# Generated deterministically by seda-macro-lef-normalizer-v1; recipe orfs-ng45-fakeram-metal3-coupledl2-pg-v1.
VERSION 5.8 ;
BUSBITCHARS "[]" ;
DIVIDERCHAR "/" ;

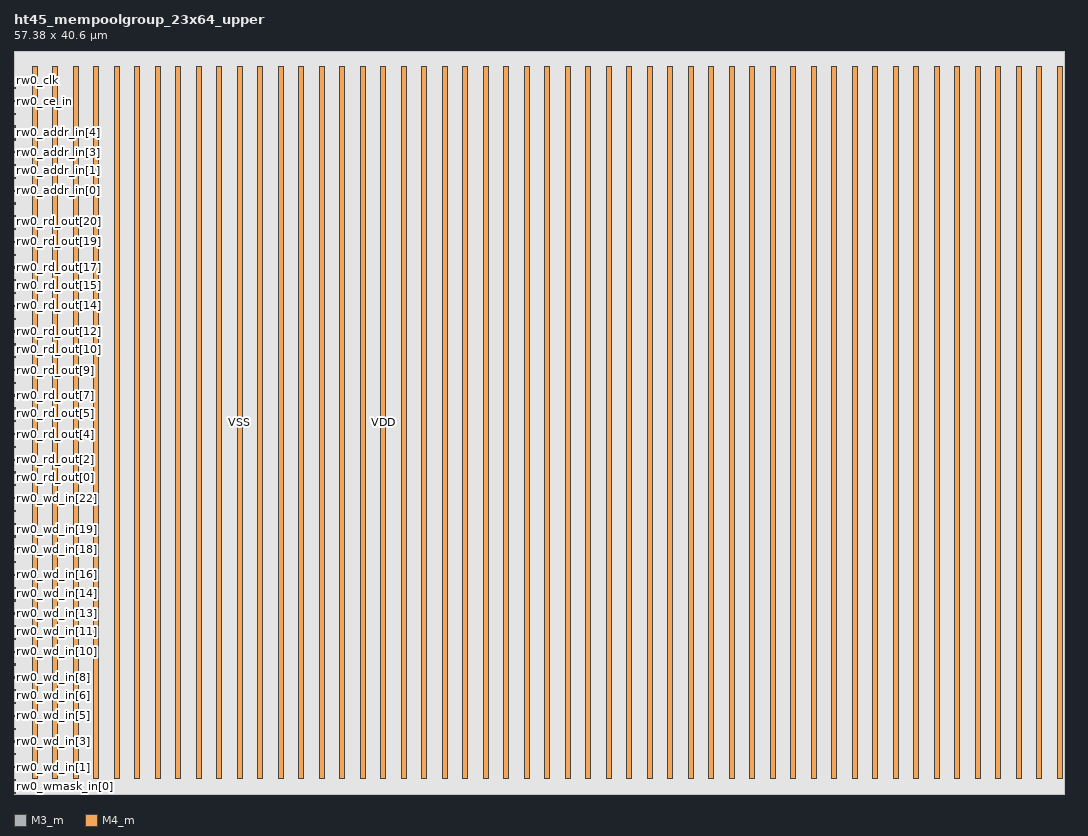
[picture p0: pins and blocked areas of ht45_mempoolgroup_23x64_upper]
MACRO ht45_mempoolgroup_23x64_upper
  FOREIGN ht45_mempoolgroup_23x64_upper 0 0 ;
  CLASS COVER ;
  ORIGIN 0 0 ;
  SIZE 57.38 BY 40.6 ;
  SYMMETRY X Y R90 ;
  PIN rw0_wmask_in[0]
    DIRECTION INPUT ;
    USE SIGNAL ;
    SHAPE ABUTMENT ;
    PORT
      LAYER M3_m ;
      RECT 0 0.035 0.07 0.105 ;
    END
  END rw0_wmask_in[0]
  PIN rw0_wd_in[0]
    DIRECTION INPUT ;
    USE SIGNAL ;
    SHAPE ABUTMENT ;
    PORT
      LAYER M3_m ;
      RECT 0 0.735 0.07 0.805 ;
    END
  END rw0_wd_in[0]
  PIN rw0_wd_in[1]
    DIRECTION INPUT ;
    USE SIGNAL ;
    SHAPE ABUTMENT ;
    PORT
      LAYER M3_m ;
      RECT 0 1.435 0.07 1.505 ;
    END
  END rw0_wd_in[1]
  PIN rw0_wd_in[2]
    DIRECTION INPUT ;
    USE SIGNAL ;
    SHAPE ABUTMENT ;
    PORT
      LAYER M3_m ;
      RECT 0 2.135 0.07 2.205 ;
    END
  END rw0_wd_in[2]
  PIN rw0_wd_in[3]
    DIRECTION INPUT ;
    USE SIGNAL ;
    SHAPE ABUTMENT ;
    PORT
      LAYER M3_m ;
      RECT 0 2.835 0.07 2.905 ;
    END
  END rw0_wd_in[3]
  PIN rw0_wd_in[4]
    DIRECTION INPUT ;
    USE SIGNAL ;
    SHAPE ABUTMENT ;
    PORT
      LAYER M3_m ;
      RECT 0 3.535 0.07 3.605 ;
    END
  END rw0_wd_in[4]
  PIN rw0_wd_in[5]
    DIRECTION INPUT ;
    USE SIGNAL ;
    SHAPE ABUTMENT ;
    PORT
      LAYER M3_m ;
      RECT 0 4.235 0.07 4.305 ;
    END
  END rw0_wd_in[5]
  PIN rw0_wd_in[6]
    DIRECTION INPUT ;
    USE SIGNAL ;
    SHAPE ABUTMENT ;
    PORT
      LAYER M3_m ;
      RECT 0 4.935 0.07 5.005 ;
    END
  END rw0_wd_in[6]
  PIN rw0_wd_in[7]
    DIRECTION INPUT ;
    USE SIGNAL ;
    SHAPE ABUTMENT ;
    PORT
      LAYER M3_m ;
      RECT 0 5.635 0.07 5.705 ;
    END
  END rw0_wd_in[7]
  PIN rw0_wd_in[8]
    DIRECTION INPUT ;
    USE SIGNAL ;
    SHAPE ABUTMENT ;
    PORT
      LAYER M3_m ;
      RECT 0 6.335 0.07 6.405 ;
    END
  END rw0_wd_in[8]
  PIN rw0_wd_in[9]
    DIRECTION INPUT ;
    USE SIGNAL ;
    SHAPE ABUTMENT ;
    PORT
      LAYER M3_m ;
      RECT 0 7.035 0.07 7.105 ;
    END
  END rw0_wd_in[9]
  PIN rw0_wd_in[10]
    DIRECTION INPUT ;
    USE SIGNAL ;
    SHAPE ABUTMENT ;
    PORT
      LAYER M3_m ;
      RECT 0 7.735 0.07 7.805 ;
    END
  END rw0_wd_in[10]
  PIN rw0_wd_in[11]
    DIRECTION INPUT ;
    USE SIGNAL ;
    SHAPE ABUTMENT ;
    PORT
      LAYER M3_m ;
      RECT 0 8.435 0.07 8.505 ;
    END
  END rw0_wd_in[11]
  PIN rw0_wd_in[12]
    DIRECTION INPUT ;
    USE SIGNAL ;
    SHAPE ABUTMENT ;
    PORT
      LAYER M3_m ;
      RECT 0 9.135 0.07 9.205 ;
    END
  END rw0_wd_in[12]
  PIN rw0_wd_in[13]
    DIRECTION INPUT ;
    USE SIGNAL ;
    SHAPE ABUTMENT ;
    PORT
      LAYER M3_m ;
      RECT 0 9.835 0.07 9.905 ;
    END
  END rw0_wd_in[13]
  PIN rw0_wd_in[14]
    DIRECTION INPUT ;
    USE SIGNAL ;
    SHAPE ABUTMENT ;
    PORT
      LAYER M3_m ;
      RECT 0 10.535 0.07 10.605 ;
    END
  END rw0_wd_in[14]
  PIN rw0_wd_in[15]
    DIRECTION INPUT ;
    USE SIGNAL ;
    SHAPE ABUTMENT ;
    PORT
      LAYER M3_m ;
      RECT 0 11.235 0.07 11.305 ;
    END
  END rw0_wd_in[15]
  PIN rw0_wd_in[16]
    DIRECTION INPUT ;
    USE SIGNAL ;
    SHAPE ABUTMENT ;
    PORT
      LAYER M3_m ;
      RECT 0 11.935 0.07 12.005 ;
    END
  END rw0_wd_in[16]
  PIN rw0_wd_in[17]
    DIRECTION INPUT ;
    USE SIGNAL ;
    SHAPE ABUTMENT ;
    PORT
      LAYER M3_m ;
      RECT 0 12.635 0.07 12.705 ;
    END
  END rw0_wd_in[17]
  PIN rw0_wd_in[18]
    DIRECTION INPUT ;
    USE SIGNAL ;
    SHAPE ABUTMENT ;
    PORT
      LAYER M3_m ;
      RECT 0 13.335 0.07 13.405 ;
    END
  END rw0_wd_in[18]
  PIN rw0_wd_in[19]
    DIRECTION INPUT ;
    USE SIGNAL ;
    SHAPE ABUTMENT ;
    PORT
      LAYER M3_m ;
      RECT 0 14.035 0.07 14.105 ;
    END
  END rw0_wd_in[19]
  PIN rw0_wd_in[20]
    DIRECTION INPUT ;
    USE SIGNAL ;
    SHAPE ABUTMENT ;
    PORT
      LAYER M3_m ;
      RECT 0 14.735 0.07 14.805 ;
    END
  END rw0_wd_in[20]
  PIN rw0_wd_in[21]
    DIRECTION INPUT ;
    USE SIGNAL ;
    SHAPE ABUTMENT ;
    PORT
      LAYER M3_m ;
      RECT 0 15.435 0.07 15.505 ;
    END
  END rw0_wd_in[21]
  PIN rw0_wd_in[22]
    DIRECTION INPUT ;
    USE SIGNAL ;
    SHAPE ABUTMENT ;
    PORT
      LAYER M3_m ;
      RECT 0 16.135 0.07 16.205 ;
    END
  END rw0_wd_in[22]
  PIN rw0_rd_out[0]
    DIRECTION OUTPUT ;
    USE SIGNAL ;
    SHAPE ABUTMENT ;
    PORT
      LAYER M3_m ;
      RECT 0 16.835 0.07 16.905 ;
    END
  END rw0_rd_out[0]
  PIN rw0_rd_out[1]
    DIRECTION OUTPUT ;
    USE SIGNAL ;
    SHAPE ABUTMENT ;
    PORT
      LAYER M3_m ;
      RECT 0 17.535 0.07 17.605 ;
    END
  END rw0_rd_out[1]
  PIN rw0_rd_out[2]
    DIRECTION OUTPUT ;
    USE SIGNAL ;
    SHAPE ABUTMENT ;
    PORT
      LAYER M3_m ;
      RECT 0 18.235 0.07 18.305 ;
    END
  END rw0_rd_out[2]
  PIN rw0_rd_out[3]
    DIRECTION OUTPUT ;
    USE SIGNAL ;
    SHAPE ABUTMENT ;
    PORT
      LAYER M3_m ;
      RECT 0 18.935 0.07 19.005 ;
    END
  END rw0_rd_out[3]
  PIN rw0_rd_out[4]
    DIRECTION OUTPUT ;
    USE SIGNAL ;
    SHAPE ABUTMENT ;
    PORT
      LAYER M3_m ;
      RECT 0 19.635 0.07 19.705 ;
    END
  END rw0_rd_out[4]
  PIN rw0_rd_out[5]
    DIRECTION OUTPUT ;
    USE SIGNAL ;
    SHAPE ABUTMENT ;
    PORT
      LAYER M3_m ;
      RECT 0 20.335 0.07 20.405 ;
    END
  END rw0_rd_out[5]
  PIN rw0_rd_out[6]
    DIRECTION OUTPUT ;
    USE SIGNAL ;
    SHAPE ABUTMENT ;
    PORT
      LAYER M3_m ;
      RECT 0 21.035 0.07 21.105 ;
    END
  END rw0_rd_out[6]
  PIN rw0_rd_out[7]
    DIRECTION OUTPUT ;
    USE SIGNAL ;
    SHAPE ABUTMENT ;
    PORT
      LAYER M3_m ;
      RECT 0 21.735 0.07 21.805 ;
    END
  END rw0_rd_out[7]
  PIN rw0_rd_out[8]
    DIRECTION OUTPUT ;
    USE SIGNAL ;
    SHAPE ABUTMENT ;
    PORT
      LAYER M3_m ;
      RECT 0 22.435 0.07 22.505 ;
    END
  END rw0_rd_out[8]
  PIN rw0_rd_out[9]
    DIRECTION OUTPUT ;
    USE SIGNAL ;
    SHAPE ABUTMENT ;
    PORT
      LAYER M3_m ;
      RECT 0 23.135 0.07 23.205 ;
    END
  END rw0_rd_out[9]
  PIN rw0_rd_out[10]
    DIRECTION OUTPUT ;
    USE SIGNAL ;
    SHAPE ABUTMENT ;
    PORT
      LAYER M3_m ;
      RECT 0 23.835 0.07 23.905 ;
    END
  END rw0_rd_out[10]
  PIN rw0_rd_out[11]
    DIRECTION OUTPUT ;
    USE SIGNAL ;
    SHAPE ABUTMENT ;
    PORT
      LAYER M3_m ;
      RECT 0 24.535 0.07 24.605 ;
    END
  END rw0_rd_out[11]
  PIN rw0_rd_out[12]
    DIRECTION OUTPUT ;
    USE SIGNAL ;
    SHAPE ABUTMENT ;
    PORT
      LAYER M3_m ;
      RECT 0 25.235 0.07 25.305 ;
    END
  END rw0_rd_out[12]
  PIN rw0_rd_out[13]
    DIRECTION OUTPUT ;
    USE SIGNAL ;
    SHAPE ABUTMENT ;
    PORT
      LAYER M3_m ;
      RECT 0 25.935 0.07 26.005 ;
    END
  END rw0_rd_out[13]
  PIN rw0_rd_out[14]
    DIRECTION OUTPUT ;
    USE SIGNAL ;
    SHAPE ABUTMENT ;
    PORT
      LAYER M3_m ;
      RECT 0 26.635 0.07 26.705 ;
    END
  END rw0_rd_out[14]
  PIN rw0_rd_out[15]
    DIRECTION OUTPUT ;
    USE SIGNAL ;
    SHAPE ABUTMENT ;
    PORT
      LAYER M3_m ;
      RECT 0 27.335 0.07 27.405 ;
    END
  END rw0_rd_out[15]
  PIN rw0_rd_out[16]
    DIRECTION OUTPUT ;
    USE SIGNAL ;
    SHAPE ABUTMENT ;
    PORT
      LAYER M3_m ;
      RECT 0 28.035 0.07 28.105 ;
    END
  END rw0_rd_out[16]
  PIN rw0_rd_out[17]
    DIRECTION OUTPUT ;
    USE SIGNAL ;
    SHAPE ABUTMENT ;
    PORT
      LAYER M3_m ;
      RECT 0 28.735 0.07 28.805 ;
    END
  END rw0_rd_out[17]
  PIN rw0_rd_out[18]
    DIRECTION OUTPUT ;
    USE SIGNAL ;
    SHAPE ABUTMENT ;
    PORT
      LAYER M3_m ;
      RECT 0 29.435 0.07 29.505 ;
    END
  END rw0_rd_out[18]
  PIN rw0_rd_out[19]
    DIRECTION OUTPUT ;
    USE SIGNAL ;
    SHAPE ABUTMENT ;
    PORT
      LAYER M3_m ;
      RECT 0 30.135 0.07 30.205 ;
    END
  END rw0_rd_out[19]
  PIN rw0_rd_out[20]
    DIRECTION OUTPUT ;
    USE SIGNAL ;
    SHAPE ABUTMENT ;
    PORT
      LAYER M3_m ;
      RECT 0 30.835 0.07 30.905 ;
    END
  END rw0_rd_out[20]
  PIN rw0_rd_out[21]
    DIRECTION OUTPUT ;
    USE SIGNAL ;
    SHAPE ABUTMENT ;
    PORT
      LAYER M3_m ;
      RECT 0 31.535 0.07 31.605 ;
    END
  END rw0_rd_out[21]
  PIN rw0_rd_out[22]
    DIRECTION OUTPUT ;
    USE SIGNAL ;
    SHAPE ABUTMENT ;
    PORT
      LAYER M3_m ;
      RECT 0 32.235 0.07 32.305 ;
    END
  END rw0_rd_out[22]
  PIN rw0_addr_in[0]
    DIRECTION INPUT ;
    USE SIGNAL ;
    SHAPE ABUTMENT ;
    PORT
      LAYER M3_m ;
      RECT 0 32.935 0.07 33.005 ;
    END
  END rw0_addr_in[0]
  PIN rw0_addr_in[1]
    DIRECTION INPUT ;
    USE SIGNAL ;
    SHAPE ABUTMENT ;
    PORT
      LAYER M3_m ;
      RECT 0 33.635 0.07 33.705 ;
    END
  END rw0_addr_in[1]
  PIN rw0_addr_in[2]
    DIRECTION INPUT ;
    USE SIGNAL ;
    SHAPE ABUTMENT ;
    PORT
      LAYER M3_m ;
      RECT 0 34.335 0.07 34.405 ;
    END
  END rw0_addr_in[2]
  PIN rw0_addr_in[3]
    DIRECTION INPUT ;
    USE SIGNAL ;
    SHAPE ABUTMENT ;
    PORT
      LAYER M3_m ;
      RECT 0 35.035 0.07 35.105 ;
    END
  END rw0_addr_in[3]
  PIN rw0_addr_in[4]
    DIRECTION INPUT ;
    USE SIGNAL ;
    SHAPE ABUTMENT ;
    PORT
      LAYER M3_m ;
      RECT 0 35.735 0.07 35.805 ;
    END
  END rw0_addr_in[4]
  PIN rw0_addr_in[5]
    DIRECTION INPUT ;
    USE SIGNAL ;
    SHAPE ABUTMENT ;
    PORT
      LAYER M3_m ;
      RECT 0 36.435 0.07 36.505 ;
    END
  END rw0_addr_in[5]
  PIN rw0_we_in
    DIRECTION INPUT ;
    USE SIGNAL ;
    SHAPE ABUTMENT ;
    PORT
      LAYER M3_m ;
      RECT 0 37.135 0.07 37.205 ;
    END
  END rw0_we_in
  PIN rw0_ce_in
    DIRECTION INPUT ;
    USE SIGNAL ;
    SHAPE ABUTMENT ;
    PORT
      LAYER M3_m ;
      RECT 0 37.835 0.07 37.905 ;
    END
  END rw0_ce_in
  PIN rw0_clk
    DIRECTION INPUT ;
    USE SIGNAL ;
    SHAPE ABUTMENT ;
    PORT
      LAYER M3_m ;
      RECT 0 38.535 0.07 38.605 ;
    END
  END rw0_clk
  PIN VSS
    DIRECTION INOUT ;
    USE GROUND ;
    PORT
      LAYER M4_m ;
      RECT 1 0.84 1.28 39.76 ;
      RECT 3.24 0.84 3.52 39.76 ;
      RECT 5.48 0.84 5.76 39.76 ;
      RECT 7.72 0.84 8 39.76 ;
      RECT 9.96 0.84 10.24 39.76 ;
      RECT 12.2 0.84 12.48 39.76 ;
      RECT 14.44 0.84 14.72 39.76 ;
      RECT 16.68 0.84 16.96 39.76 ;
      RECT 18.92 0.84 19.2 39.76 ;
      RECT 21.16 0.84 21.44 39.76 ;
      RECT 23.4 0.84 23.68 39.76 ;
      RECT 25.64 0.84 25.92 39.76 ;
      RECT 27.88 0.84 28.16 39.76 ;
      RECT 30.12 0.84 30.4 39.76 ;
      RECT 32.36 0.84 32.64 39.76 ;
      RECT 34.6 0.84 34.88 39.76 ;
      RECT 36.84 0.84 37.12 39.76 ;
      RECT 39.08 0.84 39.36 39.76 ;
      RECT 41.32 0.84 41.6 39.76 ;
      RECT 43.56 0.84 43.84 39.76 ;
      RECT 45.8 0.84 46.08 39.76 ;
      RECT 48.04 0.84 48.32 39.76 ;
      RECT 50.28 0.84 50.56 39.76 ;
      RECT 52.52 0.84 52.8 39.76 ;
      RECT 54.76 0.84 55.04 39.76 ;
      RECT 57 0.84 57.28 39.76 ;
    END
  END VSS
  PIN VDD
    DIRECTION INOUT ;
    USE POWER ;
    PORT
      LAYER M4_m ;
      RECT 2.12 0.84 2.4 39.76 ;
      RECT 4.36 0.84 4.64 39.76 ;
      RECT 6.6 0.84 6.88 39.76 ;
      RECT 8.84 0.84 9.12 39.76 ;
      RECT 11.08 0.84 11.36 39.76 ;
      RECT 13.32 0.84 13.6 39.76 ;
      RECT 15.56 0.84 15.84 39.76 ;
      RECT 17.8 0.84 18.08 39.76 ;
      RECT 20.04 0.84 20.32 39.76 ;
      RECT 22.28 0.84 22.56 39.76 ;
      RECT 24.52 0.84 24.8 39.76 ;
      RECT 26.76 0.84 27.04 39.76 ;
      RECT 29 0.84 29.28 39.76 ;
      RECT 31.24 0.84 31.52 39.76 ;
      RECT 33.48 0.84 33.76 39.76 ;
      RECT 35.72 0.84 36 39.76 ;
      RECT 37.96 0.84 38.24 39.76 ;
      RECT 40.2 0.84 40.48 39.76 ;
      RECT 42.44 0.84 42.72 39.76 ;
      RECT 44.68 0.84 44.96 39.76 ;
      RECT 46.92 0.84 47.2 39.76 ;
      RECT 49.16 0.84 49.44 39.76 ;
      RECT 51.4 0.84 51.68 39.76 ;
      RECT 53.64 0.84 53.92 39.76 ;
      RECT 55.88 0.84 56.16 39.76 ;
    END
  END VDD
  OBS
    LAYER M1_m ;
    RECT 0 0 57.38 40.6 ;
    LAYER M2_m ;
    RECT 0 0 57.38 40.6 ;
  END
END ht45_mempoolgroup_23x64_upper

END LIBRARY
